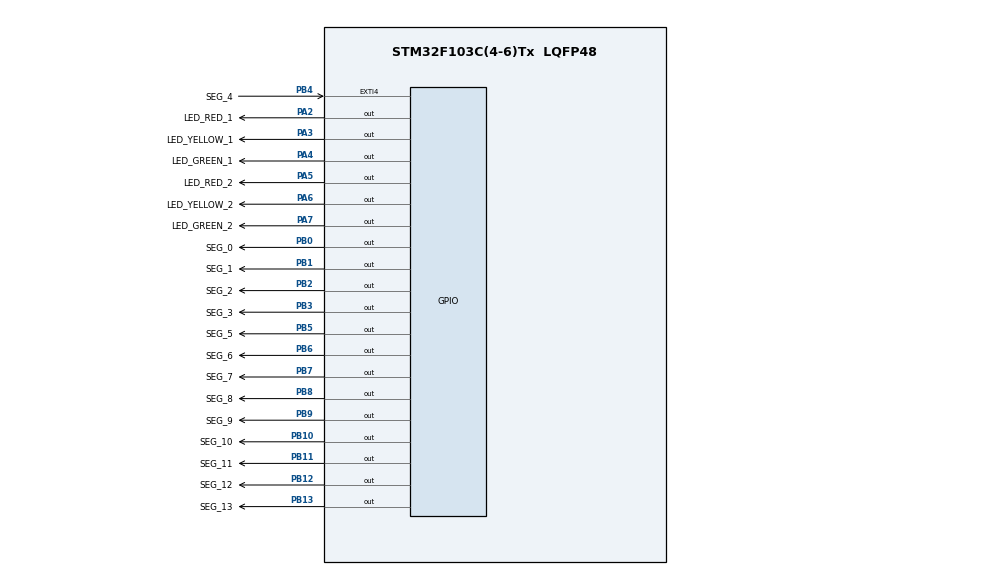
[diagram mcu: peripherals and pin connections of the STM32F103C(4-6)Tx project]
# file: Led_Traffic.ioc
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Mcu.Family=STM32F1
Mcu.Name=STM32F103C(4-6)Tx
Mcu.Package=LQFP48
NVIC.PriorityGroup=NVIC_PRIORITYGROUP_4
PA2.GPIO_Label=LED_RED_1
PA2.Signal=GPIO_Output
PA3.GPIO_Label=LED_YELLOW_1
PA3.Signal=GPIO_Output
PA4.GPIO_Label=LED_GREEN_1
PA4.Signal=GPIO_Output
PA5.GPIO_Label=LED_RED_2
PA5.Signal=GPIO_Output
PA6.GPIO_Label=LED_YELLOW_2
PA6.Signal=GPIO_Output
PA7.GPIO_Label=LED_GREEN_2
PA7.Signal=GPIO_Output
PB0.GPIO_Label=SEG_0
PB0.Signal=GPIO_Output
PB1.GPIO_Label=SEG_1
PB1.Signal=GPIO_Output
PB10.GPIO_Label=SEG_10
PB10.Signal=GPIO_Output
PB11.GPIO_Label=SEG_11
PB11.Signal=GPIO_Output
PB12.GPIO_Label=SEG_12
PB12.Signal=GPIO_Output
PB13.GPIO_Label=SEG_13
PB13.Signal=GPIO_Output
PB2.GPIO_Label=SEG_2
PB2.Signal=GPIO_Output
PB3.GPIO_Label=SEG_3
PB3.Signal=GPIO_Output
PB4.GPIO_Label=SEG_4
PB4.Signal=GPXTI4
PB5.GPIO_Label=SEG_5
PB5.Signal=GPIO_Output
PB6.GPIO_Label=SEG_6
PB6.Signal=GPIO_Output
PB7.GPIO_Label=SEG_7
PB7.Signal=GPIO_Output
PB8.GPIO_Label=SEG_8
PB8.Signal=GPIO_Output
PB9.GPIO_Label=SEG_9
PB9.Signal=GPIO_Output
ProjectManager.HeapSize=0x200
ProjectManager.StackSize=0x400
ProjectManager.TargetToolchain=STM32CubeIDE
RCC.APB1Freq_Value=8000000
RCC.APB2Freq_Value=8000000
VP_SYS_VS_ND.Mode=No_Debug
board=custom

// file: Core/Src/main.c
/* USER CODE BEGIN Header */
/**
  ******************************************************************************
  * @file           : main.c
  * @brief          : Main program body
  ******************************************************************************
  * @attention
  *
  * <h2><center>&copy; Copyright (c) 2021 STMicroelectronics.
  * All rights reserved.</center></h2>
  *
  * This software component is licensed by ST under BSD 3-Clause license,
  * the "License"; You may not use this file except in compliance with the
  * License. You may obtain a copy of the License at:
  *                        opensource.org/licenses/BSD-3-Clause
  *
  ******************************************************************************
  */
/* USER CODE END Header */
#include "main.h"

void SystemClock_Config(void);
static void MX_GPIO_Init(void);

void display7SEG(int num){
	switch (num){
	case 0:
		HAL_GPIO_WritePin(GPIOB, SEG_0_Pin ,GPIO_PIN_RESET);
		HAL_GPIO_WritePin(GPIOB, SEG_1_Pin ,GPIO_PIN_RESET);
		HAL_GPIO_WritePin(GPIOB, SEG_2_Pin ,GPIO_PIN_RESET);
		HAL_GPIO_WritePin(GPIOB, SEG_3_Pin ,GPIO_PIN_RESET);
		HAL_GPIO_WritePin(GPIOB, SEG_4_Pin ,GPIO_PIN_RESET);
		HAL_GPIO_WritePin(GPIOB, SEG_5_Pin ,GPIO_PIN_RESET);
		HAL_GPIO_WritePin(GPIOB, SEG_6_Pin ,GPIO_PIN_SET);
		break;

	case 1:
		HAL_GPIO_WritePin(GPIOB, SEG_0_Pin ,GPIO_PIN_SET);
		HAL_GPIO_WritePin(GPIOB, SEG_1_Pin ,GPIO_PIN_RESET);
		HAL_GPIO_WritePin(GPIOB, SEG_2_Pin ,GPIO_PIN_RESET);
		HAL_GPIO_WritePin(GPIOB, SEG_3_Pin ,GPIO_PIN_SET);
		HAL_GPIO_WritePin(GPIOB, SEG_4_Pin ,GPIO_PIN_SET);
		HAL_GPIO_WritePin(GPIOB, SEG_5_Pin ,GPIO_PIN_SET);
		HAL_GPIO_WritePin(GPIOB, SEG_6_Pin ,GPIO_PIN_SET);
		break;

	case 2:
		HAL_GPIO_WritePin(GPIOB, SEG_0_Pin ,GPIO_PIN_RESET);
		HAL_GPIO_WritePin(GPIOB, SEG_1_Pin ,GPIO_PIN_RESET);
		HAL_GPIO_WritePin(GPIOB, SEG_2_Pin ,GPIO_PIN_SET);
		HAL_GPIO_WritePin(GPIOB, SEG_3_Pin ,GPIO_PIN_RESET);
		HAL_GPIO_WritePin(GPIOB, SEG_4_Pin ,GPIO_PIN_RESET);
		HAL_GPIO_WritePin(GPIOB, SEG_5_Pin ,GPIO_PIN_SET);
		HAL_GPIO_WritePin(GPIOB, SEG_6_Pin ,GPIO_PIN_RESET);
		break;
	case 3:
		HAL_GPIO_WritePin(GPIOB, SEG_0_Pin ,GPIO_PIN_RESET);
		HAL_GPIO_WritePin(GPIOB, SEG_1_Pin ,GPIO_PIN_RESET);
		HAL_GPIO_WritePin(GPIOB, SEG_2_Pin ,GPIO_PIN_RESET);
		HAL_GPIO_WritePin(GPIOB, SEG_3_Pin ,GPIO_PIN_RESET);
		HAL_GPIO_WritePin(GPIOB, SEG_4_Pin ,GPIO_PIN_SET);
		HAL_GPIO_WritePin(GPIOB, SEG_5_Pin ,GPIO_PIN_SET);
		HAL_GPIO_WritePin(GPIOB, SEG_6_Pin ,GPIO_PIN_RESET);
		break;
	case 4:
		HAL_GPIO_WritePin(GPIOB, SEG_0_Pin ,GPIO_PIN_SET);
		HAL_GPIO_WritePin(GPIOB, SEG_1_Pin ,GPIO_PIN_RESET);
		HAL_GPIO_WritePin(GPIOB, SEG_2_Pin ,GPIO_PIN_RESET);
		HAL_GPIO_WritePin(GPIOB, SEG_3_Pin ,GPIO_PIN_SET);
		HAL_GPIO_WritePin(GPIOB, SEG_4_Pin ,GPIO_PIN_SET);
		HAL_GPIO_WritePin(GPIOB, SEG_5_Pin ,GPIO_PIN_RESET);
		HAL_GPIO_WritePin(GPIOB, SEG_6_Pin ,GPIO_PIN_RESET);
		break;
	case 5:
		HAL_GPIO_WritePin(GPIOB, SEG_0_Pin ,GPIO_PIN_RESET);
		HAL_GPIO_WritePin(GPIOB, SEG_1_Pin ,GPIO_PIN_SET);
		HAL_GPIO_WritePin(GPIOB, SEG_2_Pin ,GPIO_PIN_RESET);
		HAL_GPIO_WritePin(GPIOB, SEG_3_Pin ,GPIO_PIN_RESET);
		HAL_GPIO_WritePin(GPIOB, SEG_4_Pin ,GPIO_PIN_SET);
		HAL_GPIO_WritePin(GPIOB, SEG_5_Pin,GPIO_PIN_RESET);
		HAL_GPIO_WritePin(GPIOB, SEG_6_Pin ,GPIO_PIN_RESET);
		break;
	case 6:
		HAL_GPIO_WritePin(GPIOB, SEG_0_Pin ,GPIO_PIN_RESET);
		HAL_GPIO_WritePin(GPIOB, SEG_1_Pin ,GPIO_PIN_SET);
		HAL_GPIO_WritePin(GPIOB, SEG_2_Pin ,GPIO_PIN_RESET);
		HAL_GPIO_WritePin(GPIOB, SEG_3_Pin ,GPIO_PIN_RESET);
		HAL_GPIO_WritePin(GPIOB, SEG_4_Pin ,GPIO_PIN_RESET);
		HAL_GPIO_WritePin(GPIOB, SEG_5_Pin ,GPIO_PIN_RESET);
		HAL_GPIO_WritePin(GPIOB, SEG_6_Pin ,GPIO_PIN_RESET);
		break;
	case 7:
		HAL_GPIO_WritePin(GPIOB, SEG_0_Pin ,GPIO_PIN_RESET);
		HAL_GPIO_WritePin(GPIOB, SEG_1_Pin ,GPIO_PIN_RESET);
		HAL_GPIO_WritePin(GPIOB, SEG_2_Pin ,GPIO_PIN_RESET);
		HAL_GPIO_WritePin(GPIOB, SEG_3_Pin ,GPIO_PIN_SET);
		HAL_GPIO_WritePin(GPIOB, SEG_4_Pin ,GPIO_PIN_SET);
		HAL_GPIO_WritePin(GPIOB, SEG_5_Pin ,GPIO_PIN_SET);
		HAL_GPIO_WritePin(GPIOB, SEG_6_Pin ,GPIO_PIN_SET);
		break;
	case 8:
		HAL_GPIO_WritePin(GPIOB, SEG_0_Pin ,GPIO_PIN_RESET);
		HAL_GPIO_WritePin(GPIOB, SEG_1_Pin ,GPIO_PIN_RESET);
		HAL_GPIO_WritePin(GPIOB, SEG_2_Pin ,GPIO_PIN_RESET);
		HAL_GPIO_WritePin(GPIOB, SEG_3_Pin ,GPIO_PIN_RESET);
		HAL_GPIO_WritePin(GPIOB, SEG_4_Pin ,GPIO_PIN_RESET);
		HAL_GPIO_WritePin(GPIOB, SEG_5_Pin ,GPIO_PIN_RESET);
		HAL_GPIO_WritePin(GPIOB, SEG_6_Pin ,GPIO_PIN_RESET);
			break;
	case 9:
		HAL_GPIO_WritePin(GPIOB, SEG_0_Pin ,GPIO_PIN_RESET);
		HAL_GPIO_WritePin(GPIOB, SEG_1_Pin ,GPIO_PIN_RESET);
		HAL_GPIO_WritePin(GPIOB, SEG_2_Pin ,GPIO_PIN_RESET);
		HAL_GPIO_WritePin(GPIOB, SEG_3_Pin ,GPIO_PIN_RESET);
		HAL_GPIO_WritePin(GPIOB, SEG_4_Pin ,GPIO_PIN_SET);
		HAL_GPIO_WritePin(GPIOB, SEG_5_Pin ,GPIO_PIN_RESET);
		HAL_GPIO_WritePin(GPIOB, SEG_6_Pin ,GPIO_PIN_RESET);
			break;
	default:
		HAL_GPIO_WritePin(GPIOB, SEG_0_Pin ,GPIO_PIN_RESET);
		HAL_GPIO_WritePin(GPIOB, SEG_1_Pin ,GPIO_PIN_RESET);
		HAL_GPIO_WritePin(GPIOB, SEG_2_Pin ,GPIO_PIN_RESET);
		HAL_GPIO_WritePin(GPIOB, SEG_3_Pin ,GPIO_PIN_RESET);
		HAL_GPIO_WritePin(GPIOB, SEG_4_Pin ,GPIO_PIN_SET);
		HAL_GPIO_WritePin(GPIOB, SEG_5_Pin ,GPIO_PIN_RESET);
		HAL_GPIO_WritePin(GPIOB, SEG_6_Pin ,GPIO_PIN_RESET);
	}
}
void display7SEG_1(int num){
	switch (num){
	case 0:
		HAL_GPIO_WritePin(GPIOB, SEG_7_Pin ,GPIO_PIN_RESET);
		HAL_GPIO_WritePin(GPIOB, SEG_8_Pin ,GPIO_PIN_RESET);
		HAL_GPIO_WritePin(GPIOB, SEG_9_Pin ,GPIO_PIN_RESET);
		HAL_GPIO_WritePin(GPIOB, SEG_10_Pin ,GPIO_PIN_RESET);
		HAL_GPIO_WritePin(GPIOB, SEG_11_Pin ,GPIO_PIN_RESET);
		HAL_GPIO_WritePin(GPIOB, SEG_12_Pin ,GPIO_PIN_RESET);
		HAL_GPIO_WritePin(GPIOB, SEG_13_Pin ,GPIO_PIN_SET);
		break;

	case 1:
		HAL_GPIO_WritePin(GPIOB, SEG_7_Pin ,GPIO_PIN_SET);
		HAL_GPIO_WritePin(GPIOB, SEG_8_Pin ,GPIO_PIN_RESET);
		HAL_GPIO_WritePin(GPIOB, SEG_9_Pin ,GPIO_PIN_RESET);
		HAL_GPIO_WritePin(GPIOB, SEG_10_Pin ,GPIO_PIN_SET);
		HAL_GPIO_WritePin(GPIOB, SEG_11_Pin ,GPIO_PIN_SET);
		HAL_GPIO_WritePin(GPIOB, SEG_12_Pin ,GPIO_PIN_SET);
		HAL_GPIO_WritePin(GPIOB, SEG_13_Pin ,GPIO_PIN_SET);
		break;

	case 2:
		HAL_GPIO_WritePin(GPIOB, SEG_7_Pin ,GPIO_PIN_RESET);
		HAL_GPIO_WritePin(GPIOB, SEG_8_Pin ,GPIO_PIN_RESET);
		HAL_GPIO_WritePin(GPIOB, SEG_9_Pin ,GPIO_PIN_SET);
		HAL_GPIO_WritePin(GPIOB, SEG_10_Pin ,GPIO_PIN_RESET);
		HAL_GPIO_WritePin(GPIOB, SEG_11_Pin ,GPIO_PIN_RESET);
		HAL_GPIO_WritePin(GPIOB, SEG_12_Pin ,GPIO_PIN_SET);
		HAL_GPIO_WritePin(GPIOB, SEG_13_Pin ,GPIO_PIN_RESET);
		break;
	case 3:
		HAL_GPIO_WritePin(GPIOB, SEG_7_Pin ,GPIO_PIN_RESET);
		HAL_GPIO_WritePin(GPIOB, SEG_8_Pin ,GPIO_PIN_RESET);
		HAL_GPIO_WritePin(GPIOB, SEG_9_Pin ,GPIO_PIN_RESET);
		HAL_GPIO_WritePin(GPIOB, SEG_10_Pin ,GPIO_PIN_RESET);
		HAL_GPIO_WritePin(GPIOB, SEG_11_Pin ,GPIO_PIN_SET);
		HAL_GPIO_WritePin(GPIOB, SEG_12_Pin ,GPIO_PIN_SET);
		HAL_GPIO_WritePin(GPIOB, SEG_13_Pin ,GPIO_PIN_RESET);
		break;
	case 4:
		HAL_GPIO_WritePin(GPIOB, SEG_7_Pin ,GPIO_PIN_SET);
		HAL_GPIO_WritePin(GPIOB, SEG_8_Pin ,GPIO_PIN_RESET);
		HAL_GPIO_WritePin(GPIOB, SEG_9_Pin ,GPIO_PIN_RESET);
		HAL_GPIO_WritePin(GPIOB, SEG_10_Pin ,GPIO_PIN_SET);
		HAL_GPIO_WritePin(GPIOB, SEG_11_Pin ,GPIO_PIN_SET);
		HAL_GPIO_WritePin(GPIOB, SEG_12_Pin ,GPIO_PIN_RESET);
		HAL_GPIO_WritePin(GPIOB, SEG_13_Pin ,GPIO_PIN_RESET);
		break;
	case 5:
		HAL_GPIO_WritePin(GPIOB, SEG_7_Pin ,GPIO_PIN_RESET);
		HAL_GPIO_WritePin(GPIOB, SEG_8_Pin ,GPIO_PIN_SET);
		HAL_GPIO_WritePin(GPIOB, SEG_9_Pin ,GPIO_PIN_RESET);
		HAL_GPIO_WritePin(GPIOB, SEG_10_Pin ,GPIO_PIN_RESET);
		HAL_GPIO_WritePin(GPIOB, SEG_11_Pin ,GPIO_PIN_SET);
		HAL_GPIO_WritePin(GPIOB, SEG_12_Pin,GPIO_PIN_RESET);
		HAL_GPIO_WritePin(GPIOB, SEG_13_Pin ,GPIO_PIN_RESET);
		break;
	case 6:
		HAL_GPIO_WritePin(GPIOB, SEG_7_Pin ,GPIO_PIN_RESET);
		HAL_GPIO_WritePin(GPIOB, SEG_8_Pin ,GPIO_PIN_SET);
		HAL_GPIO_WritePin(GPIOB, SEG_9_Pin ,GPIO_PIN_RESET);
		HAL_GPIO_WritePin(GPIOB, SEG_10_Pin ,GPIO_PIN_RESET);
		HAL_GPIO_WritePin(GPIOB, SEG_11_Pin ,GPIO_PIN_RESET);
		HAL_GPIO_WritePin(GPIOB, SEG_12_Pin ,GPIO_PIN_RESET);
		HAL_GPIO_WritePin(GPIOB, SEG_13_Pin ,GPIO_PIN_RESET);
		break;
	case 7:
		HAL_GPIO_WritePin(GPIOB, SEG_7_Pin ,GPIO_PIN_RESET);
		HAL_GPIO_WritePin(GPIOB, SEG_8_Pin ,GPIO_PIN_RESET);
		HAL_GPIO_WritePin(GPIOB, SEG_9_Pin ,GPIO_PIN_RESET);
		HAL_GPIO_WritePin(GPIOB, SEG_10_Pin ,GPIO_PIN_SET);
		HAL_GPIO_WritePin(GPIOB, SEG_11_Pin ,GPIO_PIN_SET);
		HAL_GPIO_WritePin(GPIOB, SEG_12_Pin ,GPIO_PIN_SET);
		HAL_GPIO_WritePin(GPIOB, SEG_13_Pin ,GPIO_PIN_SET);
		break;
	case 8:
		HAL_GPIO_WritePin(GPIOB, SEG_7_Pin ,GPIO_PIN_RESET);
		HAL_GPIO_WritePin(GPIOB, SEG_8_Pin ,GPIO_PIN_RESET);
		HAL_GPIO_WritePin(GPIOB, SEG_9_Pin ,GPIO_PIN_RESET);
		HAL_GPIO_WritePin(GPIOB, SEG_10_Pin ,GPIO_PIN_RESET);
		HAL_GPIO_WritePin(GPIOB, SEG_11_Pin ,GPIO_PIN_RESET);
		HAL_GPIO_WritePin(GPIOB, SEG_12_Pin ,GPIO_PIN_RESET);
		HAL_GPIO_WritePin(GPIOB, SEG_13_Pin ,GPIO_PIN_RESET);
			break;
	case 9:
		HAL_GPIO_WritePin(GPIOB, SEG_7_Pin ,GPIO_PIN_RESET);
		HAL_GPIO_WritePin(GPIOB, SEG_8_Pin ,GPIO_PIN_RESET);
		HAL_GPIO_WritePin(GPIOB, SEG_9_Pin ,GPIO_PIN_RESET);
		HAL_GPIO_WritePin(GPIOB, SEG_10_Pin ,GPIO_PIN_RESET);
		HAL_GPIO_WritePin(GPIOB, SEG_11_Pin ,GPIO_PIN_SET);
		HAL_GPIO_WritePin(GPIOB, SEG_12_Pin ,GPIO_PIN_RESET);
		HAL_GPIO_WritePin(GPIOB, SEG_13_Pin ,GPIO_PIN_RESET);
			break;
	default:
		HAL_GPIO_WritePin(GPIOB, SEG_7_Pin ,GPIO_PIN_RESET);
		HAL_GPIO_WritePin(GPIOB, SEG_8_Pin ,GPIO_PIN_RESET);
		HAL_GPIO_WritePin(GPIOB, SEG_9_Pin ,GPIO_PIN_RESET);
		HAL_GPIO_WritePin(GPIOB, SEG_10_Pin ,GPIO_PIN_RESET);
		HAL_GPIO_WritePin(GPIOB, SEG_11_Pin ,GPIO_PIN_SET);
		HAL_GPIO_WritePin(GPIOB, SEG_12_Pin ,GPIO_PIN_RESET);
		HAL_GPIO_WritePin(GPIOB, SEG_13_Pin ,GPIO_PIN_RESET);
	}
}
int main(void)
{

  /* MCU Configuration--------------------------------------------------------*/

  /* Reset of all peripherals, Initializes the Flash interface and the Systick. */
  HAL_Init();

  /* Configure the system clock */
  SystemClock_Config();

  /* Initialize all configured peripherals */
  MX_GPIO_Init();

  /* Infinite loop */
  /* USER CODE BEGIN WHILE */
int counter=0;      //use counter
int a=0;            //use state change
int b=5;            //use state change 7SEG
int c=3;            //use state change 7SEG
int d=2;            //use state change 7SEG
while (1){
	 counter++;
     switch (a){
     case 0:
//Led Red(Led_0 PA0) OFF
//Led Yellow(Led_1 PA1) OFF
//Led Green(Led_2 PA2) ON
//Led Red_1(Led_5 PA5) ON
//Led Yellow_1(Led_6 PA6) OFF
//Led Green_1(Led_7 PA7) OFF
       HAL_GPIO_WritePin(GPIOA,LED_0_Pin,GPIO_PIN_SET);
       HAL_GPIO_WritePin(GPIOA,LED_1_Pin,GPIO_PIN_SET);
  	   HAL_GPIO_WritePin(GPIOA,LED_2_Pin,GPIO_PIN_RESET);
       HAL_GPIO_WritePin(GPIOA,LED_5_Pin,GPIO_PIN_RESET);
  	   HAL_GPIO_WritePin(GPIOA,LED_6_Pin,GPIO_PIN_SET);
  	   HAL_GPIO_WritePin(GPIOA,LED_7_Pin,GPIO_PIN_SET);
//7SEG display number 5->3
       display7SEG(b--);
//7SEG display number 3->1
  	   display7SEG_1(c--);
//When counter=3 then state change a=1
  	   if(counter==3) a=1;
  	 break;
     case 1:
//Led Red(Led_0 PA0) OFF
//Led Yellow(Led_1 PA1) OFF
//Led Green(Led_2 PA2) ON
//Led Red_1(Led_5 PA5) ON
//Led Yellow_1(Led_6 PA6) OFF
//Led Green_1(Led_7 PA7) OFF
       HAL_GPIO_WritePin(GPIOA,LED_0_Pin,GPIO_PIN_SET);
  	   HAL_GPIO_WritePin(GPIOA,LED_1_Pin,GPIO_PIN_RESET);
  	   HAL_GPIO_WritePin(GPIOA,LED_2_Pin,GPIO_PIN_SET);
  	   HAL_GPIO_WritePin(GPIOA,LED_5_Pin,GPIO_PIN_RESET);
  	   HAL_GPIO_WritePin(GPIOA,LED_6_Pin,GPIO_PIN_SET);
  	   HAL_GPIO_WritePin(GPIOA,LED_7_Pin,GPIO_PIN_SET);
//7SEG display number 2->1
  	   display7SEG(b--);
//7SEG display number 2->1
  	   display7SEG_1(d--);
//When counter=5 then state change a=2
  	   if(counter==5) a=2;
  	 break;
     case 2:
//Led Red(Led_0 PA0) ON
//Led Yellow(Led_1 PA1) OFF
//Led Green(Led_2 PA2) OFF
//Led Red_1(Led_5 PA5) OFF
//Led Yellow_1(Led_6 PA6) OFF
//Led Green_1(Led_7 PA7) ON
       HAL_GPIO_WritePin(GPIOA,LED_0_Pin,GPIO_PIN_RESET);
  	   HAL_GPIO_WritePin(GPIOA,LED_1_Pin,GPIO_PIN_SET);
  	   HAL_GPIO_WritePin(GPIOA,LED_2_Pin,GPIO_PIN_SET);
  	   HAL_GPIO_WritePin(GPIOA,LED_5_Pin,GPIO_PIN_SET);
  	   HAL_GPIO_WritePin(GPIOA,LED_6_Pin,GPIO_PIN_SET);
  	   HAL_GPIO_WritePin(GPIOA,LED_7_Pin,GPIO_PIN_RESET);
//7SEG display number 3->1
  	   display7SEG(c--);
//7SEG display number 5->3
  	   display7SEG_1(b--);
//When counter=8 then state change a=3
  	 if(counter==8) a=3;
  	 break;
     case 3:
//Led Red(Led_0 PA0) ON
//Led Yellow(Led_1 PA1) OFF
//Led Green(Led_2 PA2) OFF
//Led Red_1(Led_5 PA5) OFF
//Led Yellow_1(Led_6 PA6) ON
//Led Green_1(Led_7 PA7) OFF
       HAL_GPIO_WritePin(GPIOA,LED_0_Pin,GPIO_PIN_RESET);
  	   HAL_GPIO_WritePin(GPIOA,LED_1_Pin,GPIO_PIN_SET);
  	   HAL_GPIO_WritePin(GPIOA,LED_2_Pin,GPIO_PIN_SET);
  	   HAL_GPIO_WritePin(GPIOA,LED_5_Pin,GPIO_PIN_SET);
  	   HAL_GPIO_WritePin(GPIOA,LED_6_Pin,GPIO_PIN_RESET);
  	   HAL_GPIO_WritePin(GPIOA,LED_7_Pin,GPIO_PIN_SET);
//7SEG display number 2->1
 	   display7SEG(d--);
//7SEG display number 2->1
  	   display7SEG_1(b--);
//When counter=10 then state change a=0 and counter=0
  	  if(counter==10){
  	   a=0;
  	   counter=0;
  	  }
  	  	break;
    }
  	if(b==0) b=5;
  	if(c==0) c=3;
  	if(d==0) d=2;
  	HAL_Delay(1000);
    /* USER CODE END WHILE */

 }
}

void SystemClock_Config(void)
{
  RCC_OscInitTypeDef RCC_OscInitStruct = {0};
  RCC_ClkInitTypeDef RCC_ClkInitStruct = {0};

  /** Initializes the RCC Oscillators according to the specified parameters
  * in the RCC_OscInitTypeDef structure.
  */
  RCC_OscInitStruct.OscillatorType = RCC_OSCILLATORTYPE_HSI;
  RCC_OscInitStruct.HSIState = RCC_HSI_ON;
  RCC_OscInitStruct.HSICalibrationValue = RCC_HSICALIBRATION_DEFAULT;
  RCC_OscInitStruct.PLL.PLLState = RCC_PLL_NONE;
  if (HAL_RCC_OscConfig(&RCC_OscInitStruct) != HAL_OK)
  {
    Error_Handler();
  }
  /** Initializes the CPU, AHB and APB buses clocks
  */
  RCC_ClkInitStruct.ClockType = RCC_CLOCKTYPE_HCLK|RCC_CLOCKTYPE_SYSCLK
                              |RCC_CLOCKTYPE_PCLK1|RCC_CLOCKTYPE_PCLK2;
  RCC_ClkInitStruct.SYSCLKSource = RCC_SYSCLKSOURCE_HSI;
  RCC_ClkInitStruct.AHBCLKDivider = RCC_SYSCLK_DIV1;
  RCC_ClkInitStruct.APB1CLKDivider = RCC_HCLK_DIV1;
  RCC_ClkInitStruct.APB2CLKDivider = RCC_HCLK_DIV1;

  if (HAL_RCC_ClockConfig(&RCC_ClkInitStruct, FLASH_LATENCY_0) != HAL_OK)
  {
    Error_Handler();
  }
}

static void MX_GPIO_Init(void)
{
  GPIO_InitTypeDef GPIO_InitStruct = {0};

  /* GPIO Ports Clock Enable */
  __HAL_RCC_GPIOA_CLK_ENABLE();
  __HAL_RCC_GPIOB_CLK_ENABLE();

  /*Configure GPIO pin Output Level */
  HAL_GPIO_WritePin(GPIOA, LED_0_Pin|LED_1_Pin|LED_2_Pin|LED_5_Pin
                          |LED_6_Pin|LED_7_Pin|LED_9_Pin, GPIO_PIN_RESET);

  /*Configure GPIO pin Output Level */
  HAL_GPIO_WritePin(GPIOB, SEG_0_Pin|SEG_1_Pin|SEG_2_Pin|SEG_10_Pin
                          |SEG_11_Pin|SEG_12_Pin|SEG_13_Pin|SEG_3_Pin
                          |SEG_4_Pin|SEG_5_Pin|SEG_6_Pin|SEG_7_Pin
                          |SEG_8_Pin|SEG_9_Pin, GPIO_PIN_RESET);

  /*Configure GPIO pins : LED_0_Pin LED_1_Pin LED_2_Pin LED_5_Pin
                           LED_6_Pin LED_7_Pin LED_9_Pin */
  GPIO_InitStruct.Pin = LED_0_Pin|LED_1_Pin|LED_2_Pin|LED_5_Pin
                          |LED_6_Pin|LED_7_Pin|LED_9_Pin;
  GPIO_InitStruct.Mode = GPIO_MODE_OUTPUT_PP;
  GPIO_InitStruct.Pull = GPIO_NOPULL;
  GPIO_InitStruct.Speed = GPIO_SPEED_FREQ_LOW;
  HAL_GPIO_Init(GPIOA, &GPIO_InitStruct);

  /*Configure GPIO pins : SEG_0_Pin SEG_1_Pin SEG_2_Pin SEG_10_Pin
                           SEG_11_Pin SEG_12_Pin SEG_13_Pin SEG_3_Pin
                           SEG_4_Pin SEG_5_Pin SEG_6_Pin SEG_7_Pin
                           SEG_8_Pin SEG_9_Pin */
  GPIO_InitStruct.Pin = SEG_0_Pin|SEG_1_Pin|SEG_2_Pin|SEG_10_Pin
                          |SEG_11_Pin|SEG_12_Pin|SEG_13_Pin|SEG_3_Pin
                          |SEG_4_Pin|SEG_5_Pin|SEG_6_Pin|SEG_7_Pin
                          |SEG_8_Pin|SEG_9_Pin;
  GPIO_InitStruct.Mode = GPIO_MODE_OUTPUT_PP;
  GPIO_InitStruct.Pull = GPIO_NOPULL;
  GPIO_InitStruct.Speed = GPIO_SPEED_FREQ_LOW;
  HAL_GPIO_Init(GPIOB, &GPIO_InitStruct);

}

void Error_Handler(void)
{
  __disable_irq();
  while (1)
  {
  }
}

/************************ (C) COPYRIGHT STMicroelectronics *****END OF FILE****/
